One B-rep face of a CAD part: STEP entity #844131.
In plain terms, the planar face has unit normal (-0.656, 0, 0.755).
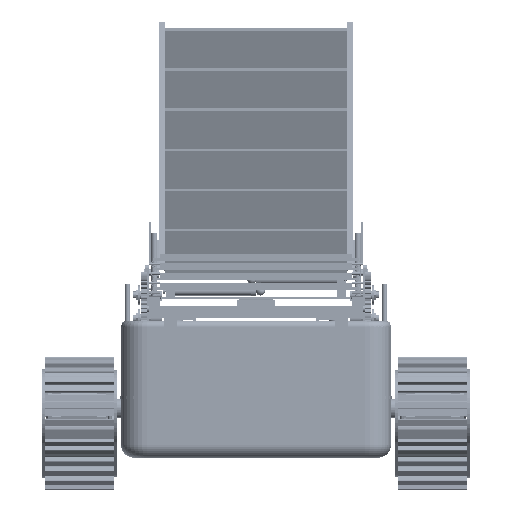
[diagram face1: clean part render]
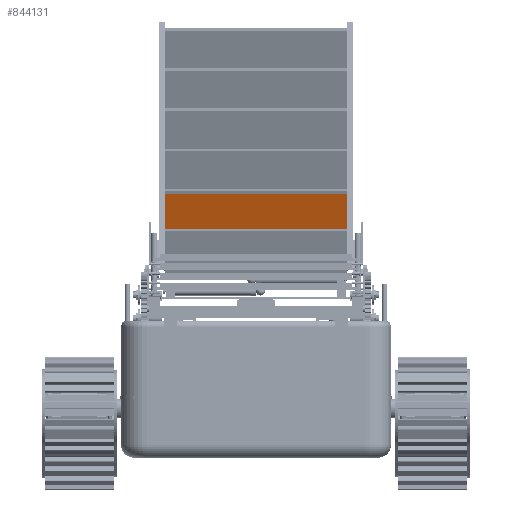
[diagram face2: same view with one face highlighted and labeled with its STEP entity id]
Length unit declared in the file: centimetre
Its self-contained STEP definition (entity closure, numbers rounded to 3 decimals, lengths and spline knots to 4 decimals):
#843817 = VERTEX_POINT('',#843818);
#843818 = CARTESIAN_POINT('',(29.947,-42.5,-22.1672));
#843825 = PLANE('',#843826);
#843826 = AXIS2_PLACEMENT_3D('',#843827,#843828,#843829);
#843827 = CARTESIAN_POINT('',(31.784,-42.5,-24.2804));
#843828 = DIRECTION('',(0.755,0.,0.656));
#843829 = DIRECTION('',(-0.656,0.,0.755));
#843837 = PLANE('',#843838);
#843838 = AXIS2_PLACEMENT_3D('',#843839,#843840,#843841);
#843839 = CARTESIAN_POINT('',(31.784,-42.5,-24.2804));
#843840 = DIRECTION('',(0.,1.,0.));
#843841 = DIRECTION('',(-0.656,0.,0.755));
#843878 = VERTEX_POINT('',#843879);
#843879 = CARTESIAN_POINT('',(29.947,42.5,-22.1672));
#843893 = PLANE('',#843894);
#843894 = AXIS2_PLACEMENT_3D('',#843895,#843896,#843897);
#843895 = CARTESIAN_POINT('',(31.784,42.5,-24.2804));
#843896 = DIRECTION('',(0.,1.,0.));
#843897 = DIRECTION('',(-0.656,0.,0.755));
#843905 = EDGE_CURVE('',#843817,#843878,#843906,.T.);
#843906 = SURFACE_CURVE('',#843907,(#843911,#843918),.PCURVE_S1.);
#843907 = LINE('',#843908,#843909);
#843908 = CARTESIAN_POINT('',(29.947,-42.5,-22.1672));
#843909 = VECTOR('',#843910,0.1);
#843910 = DIRECTION('',(0.,1.,0.));
#843911 = PCURVE('',#843825,#843912);
#843912 = DEFINITIONAL_REPRESENTATION('',(#843913),#843917);
#843913 = LINE('',#843914,#843915);
#843914 = CARTESIAN_POINT('',(2.8,0.));
#843915 = VECTOR('',#843916,1.);
#843916 = DIRECTION('',(0.,-1.));
#843917 = ( GEOMETRIC_REPRESENTATION_CONTEXT(2) 
PARAMETRIC_REPRESENTATION_CONTEXT() REPRESENTATION_CONTEXT('2D SPACE',''
  ) );
#843918 = PCURVE('',#843919,#843924);
#843919 = PLANE('',#843920);
#843920 = AXIS2_PLACEMENT_3D('',#843921,#843922,#843923);
#843921 = CARTESIAN_POINT('',(29.947,-42.5,-22.1672));
#843922 = DIRECTION('',(-0.656,0.,0.755));
#843923 = DIRECTION('',(0.755,0.,0.656));
#843924 = DEFINITIONAL_REPRESENTATION('',(#843925),#843929);
#843925 = LINE('',#843926,#843927);
#843926 = CARTESIAN_POINT('',(0.,0.));
#843927 = VECTOR('',#843928,1.);
#843928 = DIRECTION('',(0.,1.));
#843929 = ( GEOMETRIC_REPRESENTATION_CONTEXT(2) 
PARAMETRIC_REPRESENTATION_CONTEXT() REPRESENTATION_CONTEXT('2D SPACE',''
  ) );
#843937 = VERTEX_POINT('',#843938);
#843938 = CARTESIAN_POINT('',(44.2865,-42.5,-9.7021));
#843945 = PLANE('',#843946);
#843946 = AXIS2_PLACEMENT_3D('',#843947,#843948,#843949);
#843947 = CARTESIAN_POINT('',(46.1235,-42.5,-11.8153));
#843948 = DIRECTION('',(0.755,0.,0.656));
#843949 = DIRECTION('',(-0.656,0.,0.755));
#843988 = VERTEX_POINT('',#843989);
#843989 = CARTESIAN_POINT('',(44.2865,42.5,-9.7021));
#844010 = EDGE_CURVE('',#843937,#843988,#844011,.T.);
#844011 = SURFACE_CURVE('',#844012,(#844016,#844023),.PCURVE_S1.);
#844012 = LINE('',#844013,#844014);
#844013 = CARTESIAN_POINT('',(44.2865,-42.5,-9.7021));
#844014 = VECTOR('',#844015,0.1);
#844015 = DIRECTION('',(0.,1.,0.));
#844016 = PCURVE('',#843945,#844017);
#844017 = DEFINITIONAL_REPRESENTATION('',(#844018),#844022);
#844018 = LINE('',#844019,#844020);
#844019 = CARTESIAN_POINT('',(2.8,0.));
#844020 = VECTOR('',#844021,1.);
#844021 = DIRECTION('',(0.,-1.));
#844022 = ( GEOMETRIC_REPRESENTATION_CONTEXT(2) 
PARAMETRIC_REPRESENTATION_CONTEXT() REPRESENTATION_CONTEXT('2D SPACE',''
  ) );
#844023 = PCURVE('',#843919,#844024);
#844024 = DEFINITIONAL_REPRESENTATION('',(#844025),#844029);
#844025 = LINE('',#844026,#844027);
#844026 = CARTESIAN_POINT('',(19.,0.));
#844027 = VECTOR('',#844028,1.);
#844028 = DIRECTION('',(0.,1.));
#844029 = ( GEOMETRIC_REPRESENTATION_CONTEXT(2) 
PARAMETRIC_REPRESENTATION_CONTEXT() REPRESENTATION_CONTEXT('2D SPACE',''
  ) );
#844056 = EDGE_CURVE('',#843817,#843937,#844057,.T.);
#844057 = SURFACE_CURVE('',#844058,(#844062,#844069),.PCURVE_S1.);
#844058 = LINE('',#844059,#844060);
#844059 = CARTESIAN_POINT('',(29.947,-42.5,-22.1672));
#844060 = VECTOR('',#844061,0.1);
#844061 = DIRECTION('',(0.755,0.,0.656));
#844062 = PCURVE('',#843837,#844063);
#844063 = DEFINITIONAL_REPRESENTATION('',(#844064),#844068);
#844064 = LINE('',#844065,#844066);
#844065 = CARTESIAN_POINT('',(2.8,0.));
#844066 = VECTOR('',#844067,1.);
#844067 = DIRECTION('',(0.,1.));
#844068 = ( GEOMETRIC_REPRESENTATION_CONTEXT(2) 
PARAMETRIC_REPRESENTATION_CONTEXT() REPRESENTATION_CONTEXT('2D SPACE',''
  ) );
#844069 = PCURVE('',#843919,#844070);
#844070 = DEFINITIONAL_REPRESENTATION('',(#844071),#844075);
#844071 = LINE('',#844072,#844073);
#844072 = CARTESIAN_POINT('',(0.,0.));
#844073 = VECTOR('',#844074,1.);
#844074 = DIRECTION('',(1.,0.));
#844075 = ( GEOMETRIC_REPRESENTATION_CONTEXT(2) 
PARAMETRIC_REPRESENTATION_CONTEXT() REPRESENTATION_CONTEXT('2D SPACE',''
  ) );
#844103 = EDGE_CURVE('',#843878,#843988,#844104,.T.);
#844104 = SURFACE_CURVE('',#844105,(#844109,#844116),.PCURVE_S1.);
#844105 = LINE('',#844106,#844107);
#844106 = CARTESIAN_POINT('',(29.947,42.5,-22.1672));
#844107 = VECTOR('',#844108,0.1);
#844108 = DIRECTION('',(0.755,0.,0.656));
#844109 = PCURVE('',#843893,#844110);
#844110 = DEFINITIONAL_REPRESENTATION('',(#844111),#844115);
#844111 = LINE('',#844112,#844113);
#844112 = CARTESIAN_POINT('',(2.8,0.));
#844113 = VECTOR('',#844114,1.);
#844114 = DIRECTION('',(0.,1.));
#844115 = ( GEOMETRIC_REPRESENTATION_CONTEXT(2) 
PARAMETRIC_REPRESENTATION_CONTEXT() REPRESENTATION_CONTEXT('2D SPACE',''
  ) );
#844116 = PCURVE('',#843919,#844117);
#844117 = DEFINITIONAL_REPRESENTATION('',(#844118),#844122);
#844118 = LINE('',#844119,#844120);
#844119 = CARTESIAN_POINT('',(0.,85.));
#844120 = VECTOR('',#844121,1.);
#844121 = DIRECTION('',(1.,0.));
#844122 = ( GEOMETRIC_REPRESENTATION_CONTEXT(2) 
PARAMETRIC_REPRESENTATION_CONTEXT() REPRESENTATION_CONTEXT('2D SPACE',''
  ) );
#844131 = ADVANCED_FACE('',(#844132),#843919,.T.);
#844132 = FACE_BOUND('',#844133,.T.);
#844133 = EDGE_LOOP('',(#844134,#844135,#844136,#844137));
#844134 = ORIENTED_EDGE('',*,*,#843905,.F.);
#844135 = ORIENTED_EDGE('',*,*,#844056,.T.);
#844136 = ORIENTED_EDGE('',*,*,#844010,.T.);
#844137 = ORIENTED_EDGE('',*,*,#844103,.F.);
